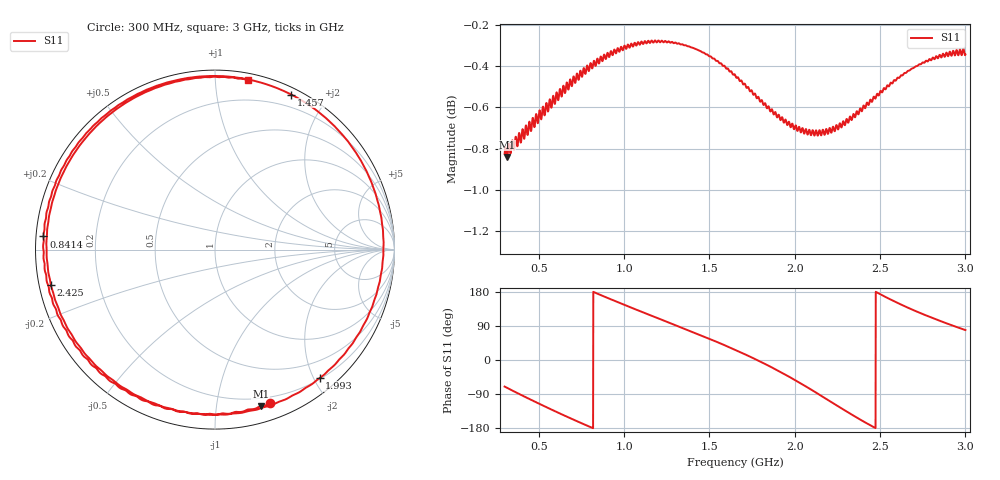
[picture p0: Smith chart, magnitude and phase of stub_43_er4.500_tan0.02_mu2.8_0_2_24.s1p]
! Chirptenna · simulación 3D de un stub abierto
# HZ S RI R 50
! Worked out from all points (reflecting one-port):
!   2001 points, 300 MHz to 3 GHz, reference 50 ohm
!   lowest |S11| = -0.8 dB at 314.9 MHz (marker M1), VSWR 20.68, Z = 6.69 - j66.3 ohm
!   phase of S11 starts at -70 deg and turns -571 deg over the sweep
!   S11 on the Smith chart (normalised r, x): 300 MHz: 0.14, -1.42; 841.4 MHz: 0.02, +0.04; 1.457 GHz: 0.07, +1.60; 1.993 GHz: 0.22, -2.09; 2.425 GHz: 0.03, -0.11; 3 GHz: 0.05, +1.21
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3e8  0.3092 -0.855
3.1485e8  0.2548 -0.8713
3.945e8  -0.027 -0.9146
4.728e8  -0.3015 -0.8728
5.5245e8  -0.5502 -0.7516
6.375e8  -0.7586 -0.5556
7.3605e8  -0.9107 -0.2647
8.4135e8  -0.9559 0.0733
9.75e8  -0.8382 0.4744
1.15185e9  -0.4612 0.8505
1.3125e9  0.0013 0.9671
1.45695e9  0.424 0.8641
1.5528e9  0.6656 0.6881
1.65e9  0.847 0.4311
1.73775e9  0.9303 0.146
1.8201e9  0.923 -0.1468
1.89975e9  0.8231 -0.4294
1.9875e9  0.6013 -0.7023
1.9929e9  0.5826 -0.7153
2.0766e9  0.2708 -0.8784
2.15625e9  -0.0759 -0.9157
2.23455e9  -0.4122 -0.8235
2.325e9  -0.7269 -0.5776
2.4249e9  -0.9145 -0.1981
2.5329e9  -0.9153 0.226
2.6625e9  -0.7096 0.6353
2.8218e9  -0.3011 0.9105
3e9  0.183 0.9437
